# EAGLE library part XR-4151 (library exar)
VOLTAGE/FREQUENCY CONVERTER

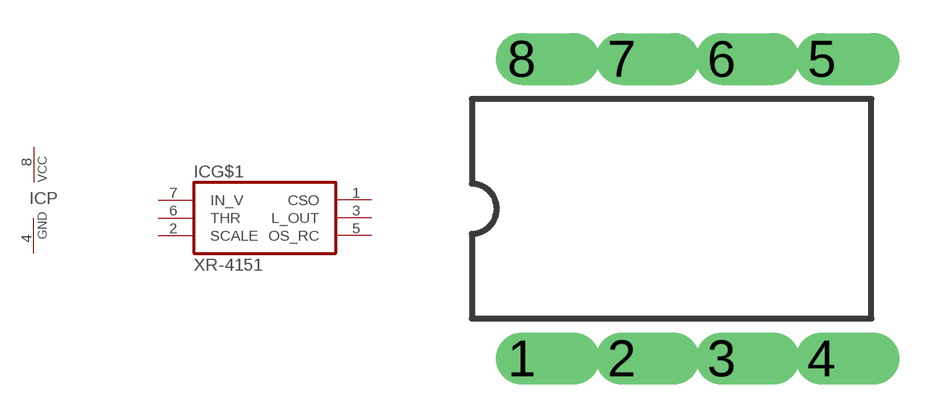
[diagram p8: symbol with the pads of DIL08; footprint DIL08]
Designator prefix IC; gates G$1=XR-4151 P=PWRN

## XR-4151  [DIL08]
1  G$1:CSO  out
2  G$1:SCALE  pas
3  G$1:L_OUT  out
4  P:GND  pwr
5  G$1:OS_RC  pas
6  G$1:THR  in
7  G$1:IN_V  in
8  P:VCC  pwr

## Footprint DIL08 (pad centres in mm)
Dual In Line
drill 0.813 offset: 1 -3.81,-3.81; 2 -1.27,-3.81; 3 1.27,-3.81; 4 3.81,-3.81; 5 3.81,3.81; 6 1.27,3.81; 7 -1.27,3.81; 8 -3.81,3.81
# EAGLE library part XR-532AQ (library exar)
PULSE DETECTOR

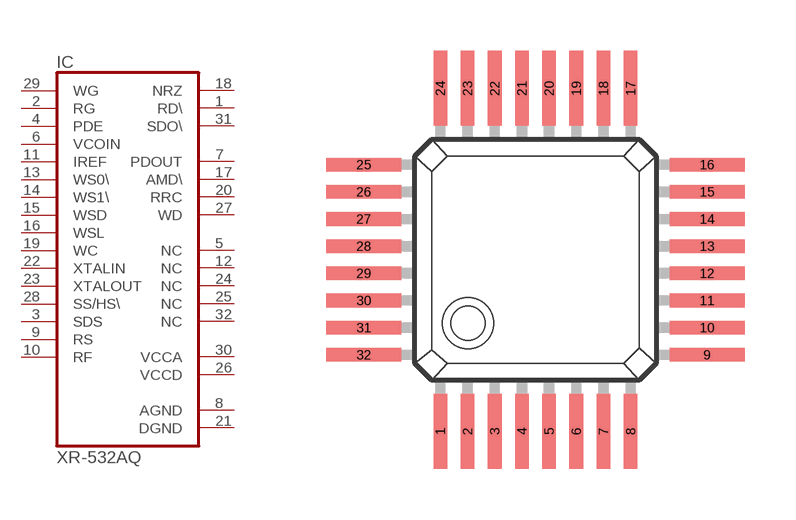
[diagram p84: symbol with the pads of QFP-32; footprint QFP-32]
Designator prefix IC

## XR-532AQ  [QFP-32]
1  RD\
2  RG  in
3  SDS  in
4  PDE  in
5  NC  nc
6  VCOIN  in
7  PDOUT  out
8  AGND  pwr
9  RS  in
10  RF  in
11  IREF  in
12  NC  nc
13  WS0\  in
14  WS1\  in
15  WSD  in
16  WSL  in
17  AMD\  out
18  NRZ
19  WC  in
20  RRC  out
21  DGND  pwr
22  XTALIN  in
23  XTALOUT  in
24  NC  nc
25  NC  nc
26  VCCD  pwr
27  WD  out
28  SS/HS\  in
29  WG  in
30  VCCA  pwr
31  SDO\
32  NC  nc

## Footprint QFP-32 (pad centres in mm)
Quad Flat Package
smd 0.4 x 2.2: 1 -2.4,-4.65; 2 -1.6,-4.65; 3 -0.8,-4.65; 4 0,-4.65; 5 0.8,-4.65; 6 1.6,-4.65; 7 2.4,-4.65; 8 3.2,-4.65; 17 3.2,5.45; 18 2.4,5.45; 19 1.6,5.45; 20 0.8,5.45; 21 0,5.45; 22 -0.8,5.45; 23 -1.6,5.45; 24 -2.4,5.45
smd 2.2 x 0.4: 9 5.45,-2.4; 10 5.45,-1.6; 11 5.45,-0.8; 12 5.45,0; 13 5.45,0.8; 14 5.45,1.6; 15 5.45,2.4; 16 5.45,3.2; 25 -4.65,3.2; 26 -4.65,2.4; 27 -4.65,1.6; 28 -4.65,0.8; 29 -4.65,0; 30 -4.65,-0.8; 31 -4.65,-1.6; 32 -4.65,-2.4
